VERSION 5.7 ;
  NOWIREEXTENSIONATPIN ON ;
  DIVIDERCHAR "/" ;
  BUSBITCHARS "[]" ;
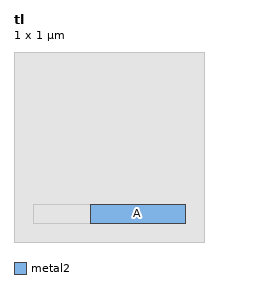
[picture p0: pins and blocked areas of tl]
MACRO tl
  CLASS BLOCK ;
  FOREIGN tl ;
  ORIGIN 0.000 0.000 ;
  SIZE 1.000 BY 1.000 ;
  PIN A
    PORT
      LAYER metal2 ;
        RECT 0.400 0.100 0.900 0.200 ;
    END
  END A
  OBS
      LAYER NWELL ;
        RECT 0.000 0.000 1.000 1.000 ;
      LAYER metal1 ;
        RECT 0.100 0.100 0.500 0.200 ;
      LAYER via1 ;
        RECT 0.400 0.100 0.500 0.200 ;
  END
END tl
END LIBRARY

